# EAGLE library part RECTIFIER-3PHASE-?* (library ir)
THREE PHASE BRIDGE Source: http://www.irf.com/product-info/datasheets/data/36mt.pdf

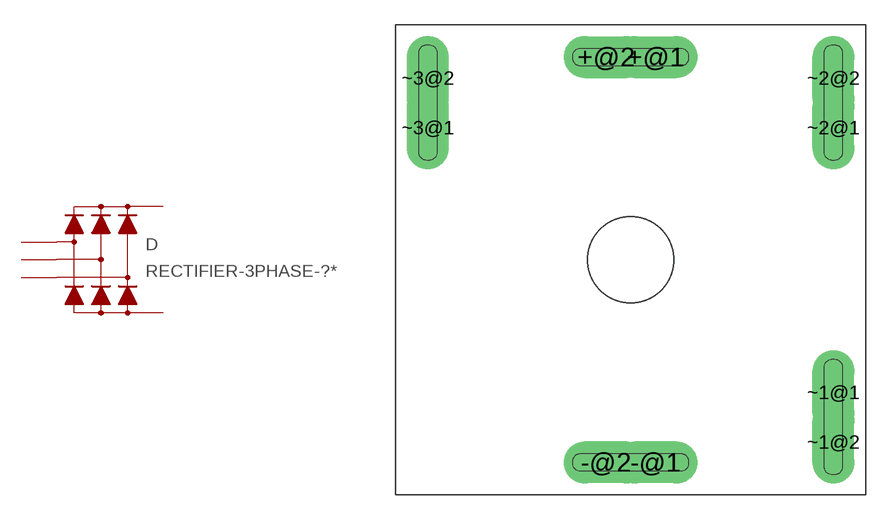
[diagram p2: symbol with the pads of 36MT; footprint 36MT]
Designator prefix D

## RECTIFIER-3PHASE-36MT10, RECTIFIER-3PHASE-36MT100, RECTIFIER-3PHASE-36MT120, RECTIFIER-3PHASE-36MT140, RECTIFIER-3PHASE-36MT160, RECTIFIER-3PHASE-36MT20, RECTIFIER-3PHASE-36MT40, RECTIFIER-3PHASE-36MT5, RECTIFIER-3PHASE-36MT60, RECTIFIER-3PHASE-36MT80  [36MT]
+@1  +  pas
+@2  +  pas
-@1  -  pas
-@2  -  pas
~1@1  ~1  pas
~1@2  ~1  pas
~2@1  ~2  pas
~2@2  ~2  pas
~3@1  ~3  pas
~3@2  ~3  pas

## Footprint 36MT (pad centres in mm)
Source: http://www.irf.com/product-info/datasheets/data/36mt.pdf
drill 1.1 pad 2.54 long: +@1 1.5,12.25; +@2 -1.5,12.25; -@1 1.5,-12.25; -@2 -1.5,-12.25; ~1@1 12.25,-8; ~1@2 12.25,-11; ~2@1 12.25,8; ~2@2 12.25,11; ~3@1 -12.25,8; ~3@2 -12.25,11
